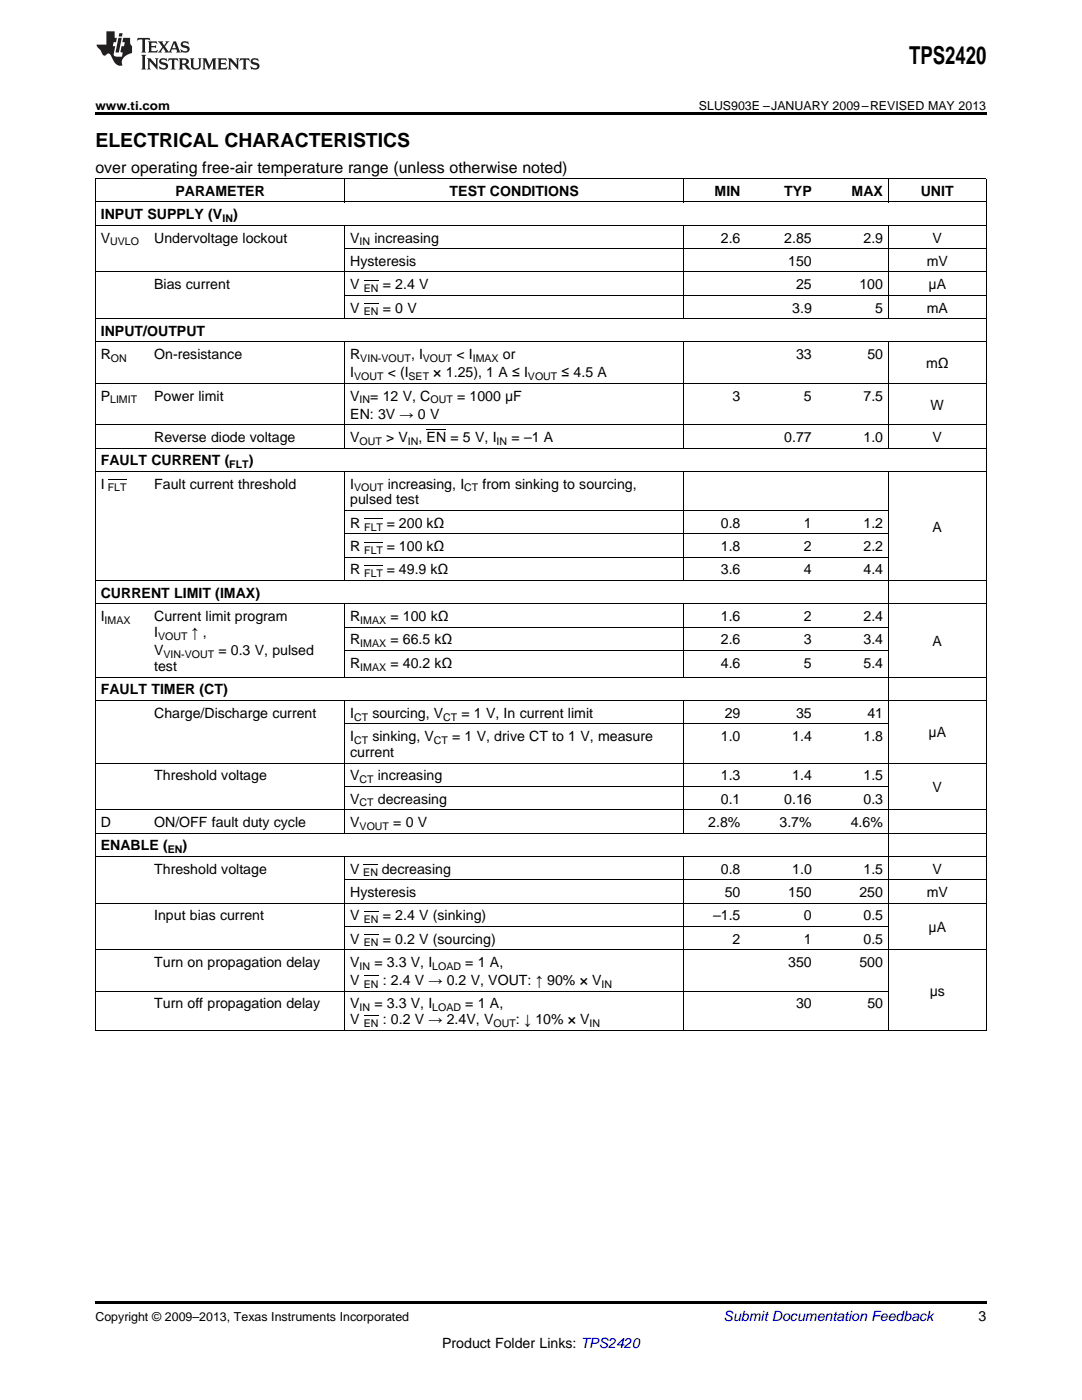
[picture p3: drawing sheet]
<svg xmlns="http://www.w3.org/2000/svg" width="216mm" height="279mm" viewBox="0 0 216 279" stroke-linecap="round" stroke-linejoin="round" font-family="sans-serif">
<defs><g id="words">
<text font-size="4.9" x="181.4" y="12.8">TPS2420</text>
<text font-size="3.9" x="19" y="29.3">ELECTRICAL CHARACTERISTICS</text>
<text font-size="3.2" x="19" y="34.4">over operating free-air temperature range (unless otherwise noted)</text>
<g font-size="2.8">
<text x="35" y="39.1">PARAMETER</text>
<text x="89.7" y="39.1">TEST CONDITIONS</text>
<text x="142.6" y="39.1">MIN</text>
<text x="156.5" y="39.1">TYP</text>
<text x="169.9" y="39.1">MAX</text>
<text x="183.7" y="39.1">UNIT</text>
<text x="20.1" y="43.7">INPUT SUPPLY (V</text>
<text x="46.5" y="43.7">)</text>
<text x="20.1" y="48.4">V</text>
<text x="30.8" y="48.4">Undervoltage lockout</text>
<text x="69.9" y="48.4">V</text>
<text x="69.9" y="53.1">Hysteresis</text>
<text x="74.7" y="48.4">increasing</text>
<text x="143.8" y="48.4">2.6</text>
<text x="156.5" y="48.4">2.85</text>
<text x="157.3" y="53.1">150</text>
<text x="172.3" y="48.4">2.9</text>
<text x="184.9" y="53.1">mV</text>
<text x="186.1" y="48.4">V</text>
<text x="30.8" y="57.7">Bias current</text>
<text x="69.9" y="57.7">V</text>
<text x="76.4" y="57.7">= 2.4 V</text>
<text x="158.9" y="57.7">25</text>
<text x="171.5" y="57.7">100</text>
<text x="185.3" y="57.7">μA</text>
<text x="69.9" y="62.4">V</text>
<text x="76.4" y="62.4">= 0 V</text>
<text x="158.1" y="62.4">3.9</text>
<text x="174.6" y="62.4">5</text>
<text x="184.9" y="62.4">mA</text>
<text x="20.1" y="67">INPUT/OUTPUT</text>
<text x="20.1" y="71.7">R</text>
<text x="30.8" y="71.7">On-resistance</text>
<text x="69.9" y="71.7">R</text>
<text x="82" y="71.7">, I</text>
<text x="91.1" y="71.7">&lt; I</text>
<text x="100.3" y="71.7">or</text>
<text x="158.9" y="71.7">33</text>
<text x="173.1" y="71.7">50</text>
<text x="69.9" y="75.3">I</text>
<text x="77.4" y="75.3">&lt; (I</text>
<text x="86.5" y="75.3">× 1.25), 1 A ≤ I</text>
<text x="112" y="75.3">≤ 4.5 A</text>
<text x="184.8" y="73.5">mΩ</text>
<text x="20.1" y="79.9">P</text>
<text x="30.8" y="79.9">Power limit</text>
<text x="69.9" y="79.9">V</text>
<text x="69.9" y="83.5">EN: 3V → 0 V</text>
<text x="73.9" y="79.9">= 12 V, C</text>
<text x="91.2" y="79.9">= 1000 μF</text>
<text x="146.2" y="79.9">3</text>
<text x="160.4" y="79.9">5</text>
<text x="172.3" y="79.9">7.5</text>
<text x="185.7" y="81.7">W</text>
<text x="30.8" y="88.2">Reverse diode voltage</text>
<text x="69.9" y="88.2">V</text>
<text x="77" y="88.2">&gt; V</text>
<text x="83.5" y="88.2">, EN = 5 V, I</text>
<text x="102.1" y="88.2">= –1 A</text>
<text x="156.5" y="88.2">0.77</text>
<text x="172.3" y="88.2">1.0</text>
<text x="186.1" y="88.2">V</text>
<text x="20.1" y="92.9">FAULT CURRENT (</text>
<text x="49.6" y="92.9">)</text>
<text x="20.1" y="97.5">I</text>
<text x="30.8" y="97.5">Fault current threshold</text>
<text x="69.9" y="97.5">I</text>
<text x="69.9" y="100.7">pulsed test</text>
<text x="77.4" y="97.5">increasing, I</text>
<text x="96.3" y="97.5">from sinking to sourcing,</text>
<text x="69.9" y="105.3">R</text>
<text x="77.2" y="105.3">= 200 kΩ</text>
<text x="143.8" y="105.3">0.8</text>
<text x="160.4" y="105.3">1</text>
<text x="172.3" y="105.3">1.2</text>
<text x="186.1" y="106.1">A</text>
<text x="69.9" y="110">R</text>
<text x="77.2" y="110">= 100 kΩ</text>
<text x="143.8" y="110">1.8</text>
<text x="160.4" y="110">2</text>
<text x="172.3" y="110">2.2</text>
<text x="20.1" y="119.3">CURRENT LIMIT (IMAX)</text>
<text x="69.9" y="114.7">R</text>
<text x="77.2" y="114.7">= 49.9 kΩ</text>
<text x="143.8" y="114.7">3.6</text>
<text x="160.4" y="114.7">4</text>
<text x="172.3" y="114.7">4.4</text>
<text x="20.1" y="124">I</text>
<text x="30.8" y="124">Current limit program</text>
<text x="69.9" y="124">R</text>
<text x="77.9" y="124">= 100 kΩ</text>
<text x="143.8" y="124">1.6</text>
<text x="160.4" y="124">2</text>
<text x="172.3" y="124">2.4</text>
<text x="30.8" y="127.1">I</text>
<text x="30.8" y="130.7">V</text>
<text x="38.2" y="127.1">↑ ,</text>
<text x="43.6" y="130.7">= 0.3 V, pulsed</text>
<text x="69.9" y="128.6">R</text>
<text x="77.9" y="128.6">= 66.5 kΩ</text>
<text x="143.8" y="128.6">2.6</text>
<text x="160.4" y="128.6">3</text>
<text x="172.3" y="128.6">3.4</text>
<text x="186.1" y="128.9">A</text>
<text x="30.8" y="133.9">test</text>
<text x="69.9" y="133.3">R</text>
<text x="77.9" y="133.3">= 40.2 kΩ</text>
<text x="143.8" y="133.3">4.6</text>
<text x="160.4" y="133.3">5</text>
<text x="172.3" y="133.3">5.4</text>
<text x="20.1" y="138.6">FAULT TIMER (CT)</text>
<text x="30.8" y="143.2">Charge/Discharge current</text>
<text x="69.9" y="143.2">I</text>
<text x="74.3" y="143.2">sourcing, V</text>
<text x="92.1" y="143.2">= 1 V, In current limit</text>
<text x="144.6" y="143.2">29</text>
<text x="158.9" y="143.2">35</text>
<text x="173.1" y="143.2">41</text>
<text x="69.9" y="147.9">I</text>
<text x="74.3" y="147.9">sinking, V</text>
<text x="90.2" y="147.9">= 1 V, drive CT to 1 V, measure</text>
<text x="143.8" y="147.9">1.0</text>
<text x="158.1" y="147.9">1.4</text>
<text x="172.3" y="147.9">1.8</text>
<text x="185.3" y="147.1">μA</text>
<text x="30.8" y="155.7">Threshold voltage</text>
<text x="69.9" y="151.1">current</text>
<text x="69.9" y="155.7">V</text>
<text x="75.4" y="155.7">increasing</text>
<text x="143.8" y="155.7">1.3</text>
<text x="158.1" y="155.7">1.4</text>
<text x="172.3" y="155.7">1.5</text>
<text x="69.9" y="160.4">V</text>
<text x="75.4" y="160.4">decreasing</text>
<text x="143.8" y="160.4">0.1</text>
<text x="156.5" y="160.4">0.16</text>
<text x="172.3" y="160.4">0.3</text>
<text x="186.1" y="158">V</text>
<text x="20.1" y="165">D</text>
<text x="30.8" y="165">ON/OFF fault duty cycle</text>
<text x="69.9" y="165">V</text>
<text x="78.5" y="165">= 0 V</text>
<text x="141.3" y="165">2.8%</text>
<text x="155.5" y="165">3.7%</text>
<text x="169.8" y="165">4.6%</text>
<text x="20.1" y="169.7">ENABLE (</text>
<text x="36.4" y="169.7">)</text>
<text x="30.8" y="174.3">Threshold voltage</text>
<text x="69.9" y="174.3">V</text>
<text x="69.9" y="179">Hysteresis</text>
<text x="76.2" y="174.3">decreasing</text>
<text x="143.8" y="174.3">0.8</text>
<text x="144.6" y="179">50</text>
<text x="157.3" y="179">150</text>
<text x="158.1" y="174.3">1.0</text>
<text x="171.5" y="179">250</text>
<text x="172.3" y="174.3">1.5</text>
<text x="184.9" y="179">mV</text>
<text x="186.1" y="174.3">V</text>
<text x="30.8" y="183.7">Input bias current</text>
<text x="69.9" y="183.7">V</text>
<text x="76.4" y="183.7">= 2.4 V (sinking)</text>
<text x="142.3" y="183.7">–1.5</text>
<text x="160.4" y="183.7">0</text>
<text x="172.3" y="183.7">0.5</text>
<text x="185.3" y="186">μA</text>
<text x="69.9" y="188.3">V</text>
<text x="76.4" y="188.3">= 0.2 V (sourcing)</text>
<text x="146.2" y="188.3">2</text>
<text x="160.4" y="188.3">1</text>
<text x="172.3" y="188.3">0.5</text>
<text x="30.8" y="193">Turn on propagation delay</text>
<text x="69.9" y="193">V</text>
<text x="69.9" y="196.6">V</text>
<text x="74.7" y="193">= 3.3 V, I</text>
<text x="76.4" y="196.6">: 2.4 V → 0.2 V, VOUT: ↑ 90% × V</text>
<text x="92.9" y="193">= 1 A,</text>
<text x="157.3" y="193">350</text>
<text x="171.5" y="193">500</text>
<text x="30.8" y="201.2">Turn off propagation delay</text>
<text x="69.9" y="201.2">V</text>
<text x="74.7" y="201.2">= 3.3 V, I</text>
<text x="92.9" y="201.2">= 1 A,</text>
<text x="158.9" y="201.2">30</text>
<text x="173.1" y="201.2">50</text>
<text x="185.5" y="198.7">μs</text>
<text x="69.9" y="204.4">V</text>
<text x="76.4" y="204.4">: 0.2 V → 2.4V, V</text>
<text x="102.9" y="204.4">: ↓ 10% × V</text>
<text x="195.3" y="263.6">3</text>
<text x="88.2" y="269">Product Folder Links: TPS2420</text>
</g>
<text font-size="2.8" fill="#0000c8" x="144.4" y="263.6">Submit Documentation Feedback</text>
<g font-size="2.5">
<text x="19" y="21.9">www.ti.com</text>
<text x="139.5" y="21.9">SLUS903E –JANUARY 2009–REVISED MAY 2013</text>
<text x="19" y="263.6">Copyright © 2009–2013, Texas Instruments Incorporated</text>
</g>
<g font-size="2.1">
<text x="44.4" y="44.3">IN</text>
<text x="22" y="49">UVLO</text>
<text x="71.8" y="49">IN</text>
<text x="72.6" y="58.3">EN</text>
<text x="72.6" y="62.9">EN</text>
<text x="22.1" y="72.2">ON</text>
<text x="70.7" y="75.8">VOUT</text>
<text x="71.9" y="72.2">VIN-VOUT</text>
<text x="81.5" y="75.8">SET</text>
<text x="84.4" y="72.2">VOUT</text>
<text x="94.3" y="72.2">IMAX</text>
<text x="105.3" y="75.8">VOUT</text>
<text x="22" y="80.5">LIMIT</text>
<text x="71.8" y="80.5">IN</text>
<text x="85.9" y="80.5">OUT</text>
<text x="71.8" y="88.8">OUT</text>
<text x="81.4" y="88.8">IN</text>
<text x="99.1" y="88.8">IN</text>
<text x="45.8" y="93.4">FLT</text>
<text x="21.5" y="98.1">FLT</text>
<text x="70.7" y="98.1">VOUT</text>
<text x="92.6" y="98.1">CT</text>
<text x="72.7" y="105.9">FLT</text>
<text x="72.7" y="110.6">FLT</text>
<text x="72.7" y="115.2">FLT</text>
<text x="20.9" y="124.5">IMAX</text>
<text x="71.9" y="124.5">IMAX</text>
<text x="31.5" y="127.7">VOUT</text>
<text x="32.6" y="131.3">VIN-VOUT</text>
<text x="71.9" y="129.2">IMAX</text>
<text x="71.9" y="133.8">IMAX</text>
<text x="70.7" y="143.8">CT</text>
<text x="88.4" y="143.8">CT</text>
<text x="70.7" y="148.4">CT</text>
<text x="86.6" y="148.4">CT</text>
<text x="71.8" y="156.3">CT</text>
<text x="71.8" y="160.9">CT</text>
<text x="71.8" y="165.6">VOUT</text>
<text x="33.5" y="170.3">EN</text>
<text x="72.5" y="174.9">EN</text>
<text x="72.6" y="184.2">EN</text>
<text x="72.6" y="188.9">EN</text>
<text x="71.8" y="193.5">IN</text>
<text x="72.6" y="197.1">EN</text>
<text x="86.3" y="193.5">LOAD</text>
<text x="120" y="197.1">IN</text>
<text x="71.8" y="201.8">IN</text>
<text x="86.3" y="201.8">LOAD</text>
<text x="72.6" y="205">EN</text>
<text x="98.5" y="205">OUT</text>
<text x="117.7" y="205">IN</text>
</g>
</g></defs>
<path d="M19 22.5h177.8v.5h-177.8zM19 259.7h177.8v.5h-177.8z" fill="#000"/>
<g fill="none" stroke="#000" stroke-width=".2">
<path d="M19 35.6h177.8M19.1 35.7v170M68.8 35.7v4.7M136.3 35.7v4.7M177.2 35.7v4.7M196.8 35.7v170M19 54.3h177.8M19 45h177.8M19 40.3h177.8M68.8 45v18.6M68.8 58.9h128M68.8 49.6h128"/>
<path d="M136.3 45v18.6M177.2 45v18.6M19 76.5h177.8M19 68.2h177.8M19 63.6h177.8M68.8 68.3v21.2M136.3 68.3v21.2M177.2 68.3v21.2M19 94.1h177.8M19 89.4h177.8M19 84.8h177.8M68.8 94.1v21.8"/>
<path d="M136.3 94.1v21.8M177.2 94.1v111.6M19 115.9h177.8M68.8 111.2h108.5M68.8 106.6h108.5M68.8 101.9h108.5M19 139.8h177.8M19 135.1h177.8M19 120.5h177.8M68.8 120.6v14.6M68.8 139.8v26.5M68.8 129.8h108.5"/>
<path d="M68.8 125.2h108.5M136.3 120.6v14.6M136.3 139.8v26.5M19 152.3h177.8M68.8 156.9h108.5M68.8 144.4h108.5M19 170.9h177.8M19 166.2h177.8M19 161.6h177.8M68.8 171v34.7M68.8 175.6h128M136.3 171v34.7"/>
<path d="M19 197.8h158.3M19 189.5h177.8M19 180.2h177.8M68.8 184.9h108.5M19 205.6h177.8"/>
</g>
<g fill="#231f20">
<path d="M27.5 7.6l-.1 .5 .4-.2h.6v.1v2.1l-.2 .4h1l-.3-.4v-2.1l.1-.1h.5l.5 .2-.2-.5zM29.5 8.3l.2 .3v1.5l-.2 .4h1.8l.2-.6a1.04 1.04 0 0 1-1.3 .2v-.7h.6l.3 .2v-.6l-.3 .2h-.6v-.6l.8-.1 .4 .3-.2-.5zM31.5 8.3l.9 1.1-.9 1.1h.8l-.2-.2 .5-.7 .4 .7-.2 .2h1.5l-.1-.2 .1-.4h.9l.1 .4-.2 .2h1l-.3-.3-.7-1.9h-.5l-.9 2-.8-1 .9-1h-.8l.1 .3-.3 .5-.4-.6 .2-.2zM34.7 8.6l.4 1h-.7zM36.3 8.4a.63 .63 0 0 0-.2 .7 .63 .63 0 0 0 .6 .4l.6 .2 .1 .2a.75 .75 0 0 1-.7 .4 .75 .75 0 0 1-.6-.5l.1 .7 .1-.1a1.11 1.11 0 0 0 1.5-.6 1.13 1.13 0 0 0-1.2-.8l-.1-.4a1.04 1.04 0 0 1 1.2 .2l-.2-.5-.1 .1-.5-.2zM28.2 10.9l.2 .4v2.2l-.2 .4h1l-.3-.4v-2.2l.3-.4zM29.3 11.6l.3 .4v1.5l-.3 .4h.8l-.2-.4v-1.3l1.5 1.7v-1.9l.2-.4h-.7l.2 .4v.9l-1.1-1.3zM32 11.8a.62 .62 0 0 0-.2 .7 .62 .62 0 0 0 .6 .4l.6 .1 .1 .3a.76 .76 0 0 1-.7 .3 .76 .76 0 0 1-.6-.4l.1 .7 .1-.1a1.11 1.11 0 0 0 1.5-.6 1.13 1.13 0 0 0-1.2-.8l-.1-.4a1.04 1.04 0 0 1 1.2 .2l-.2-.6-.1 .1-.5-.1zM33.7 11.6l-.2 .6a.61 .61 0 0 1 .8-.3v1.6l-.2 .4h.9l-.2-.4v-1.6a.63 .63 0 0 1 .8 .3l-.2-.6zM35.6 11.6l.3 .4v1.5l-.3 .4h1l-.2-.2v-.8l.5 .2a.76 .76 0 0 0 1.2 .7l-1-1a.58 .58 0 0 0 .6-.5 .58 .58 0 0 0-.5-.6zM36.4 11.9h.1a.45 .45 0 0 1 .5 .1 .45 .45 0 0 1 .1 .5l-.7 .2zM37.9 11.6l.2 .2a2.17 2.17 0 0 0 .3 1.9 .99 .99 0 0 0 1.6-.6v-1.1l.2-.4h-.7l.2 .2a1.92 1.92 0 0 1-.2 1.8 .6 .6 0 0 1-.9-.5v-1.1l.2-.4zM40.4 11.6l.2 .4v1.5l-.2 .4h.7l-.2-.4v-1.4l.8 1.8 .8-1.8v1.4l-.2 .4h.9l-.2-.4v-1.5l.2-.4h-.8l-.6 1.5-.6-1.5zM43.4 11.6l.2 .4v1.5l-.2 .4h1.8l.2-.6a1.04 1.04 0 0 1-1.3 .1v-.6h.5l.4 .2v-.6l-.4 .2h-.5v-.7h.8l.3 .3-.1-.6zM45.5 11.6l.2 .4v1.5l-.2 .4h.7l-.2-.4v-1.3l1.5 1.7v-1.9l.2-.4h-.7l.2 .4v.9l-1.1-1.3zM47.9 11.6l-.1 .6a.61 .61 0 0 1 .8-.3v1.6l-.3 .4h1l-.3-.4 .1-1.6a.63 .63 0 0 1 .7 .3l-.1-.6zM50.2 11.8a.62 .62 0 0 0-.2 .7 .62 .62 0 0 0 .6 .4l.6 .1 .2 .3a.76 .76 0 0 1-.8 .3 .76 .76 0 0 1-.6-.4l.1 .7 .2-.1a1.11 1.11 0 0 0 1.5-.6 1.13 1.13 0 0 0-1.3-.8l-.1-.4a1.04 1.04 0 0 1 1.2 .2l-.1-.6-.2 .1-.5-.1z"/>
<path d="M21.2 6.3v2.6h-1.9l.1 .4 .7 .9a.91 .91 0 0 0 1 .8 .56 .56 0 0 1 .5-.3 .56 .56 0 0 1 .5 .3l.4 .8a1.53 1.53 0 0 0 1.9 1.2 1.54 1.54 0 0 1 1-2.1l.9-.3v-1.4a1.52 1.52 0 0 1-.3-1.6h-1.4l-.2 .8h.5l-.2 .8h-.4l-.2 1v.2l.4 .1-.2 .8a1.93 1.93 0 0 1-1.6-.3l.3-1.8h-.5l.2-.8h.4l.2-.8h-.4v-1.3zM23.6 7.6l-.6 2.9h.7l.6-2.9zM23.8 6.6l-.1 .7h.6l.2-.7z"/>
</g>
<path d="M72.6 55.9h2.9M72.6 60.6h2.9M21.5 95.7h3.8M85.1 85.7h3.9M72.7 112.8h3.7M72.7 108.2h3.7M72.7 103.5h3.7M72.5 172.5h2.9M72.6 194.8h2.9M72.6 186.5h2.9M72.6 181.8h2.9M72.6 202.6h2.9" fill="none" stroke="#000" stroke-width=".2"/>
<use href="#words"/>
</svg>
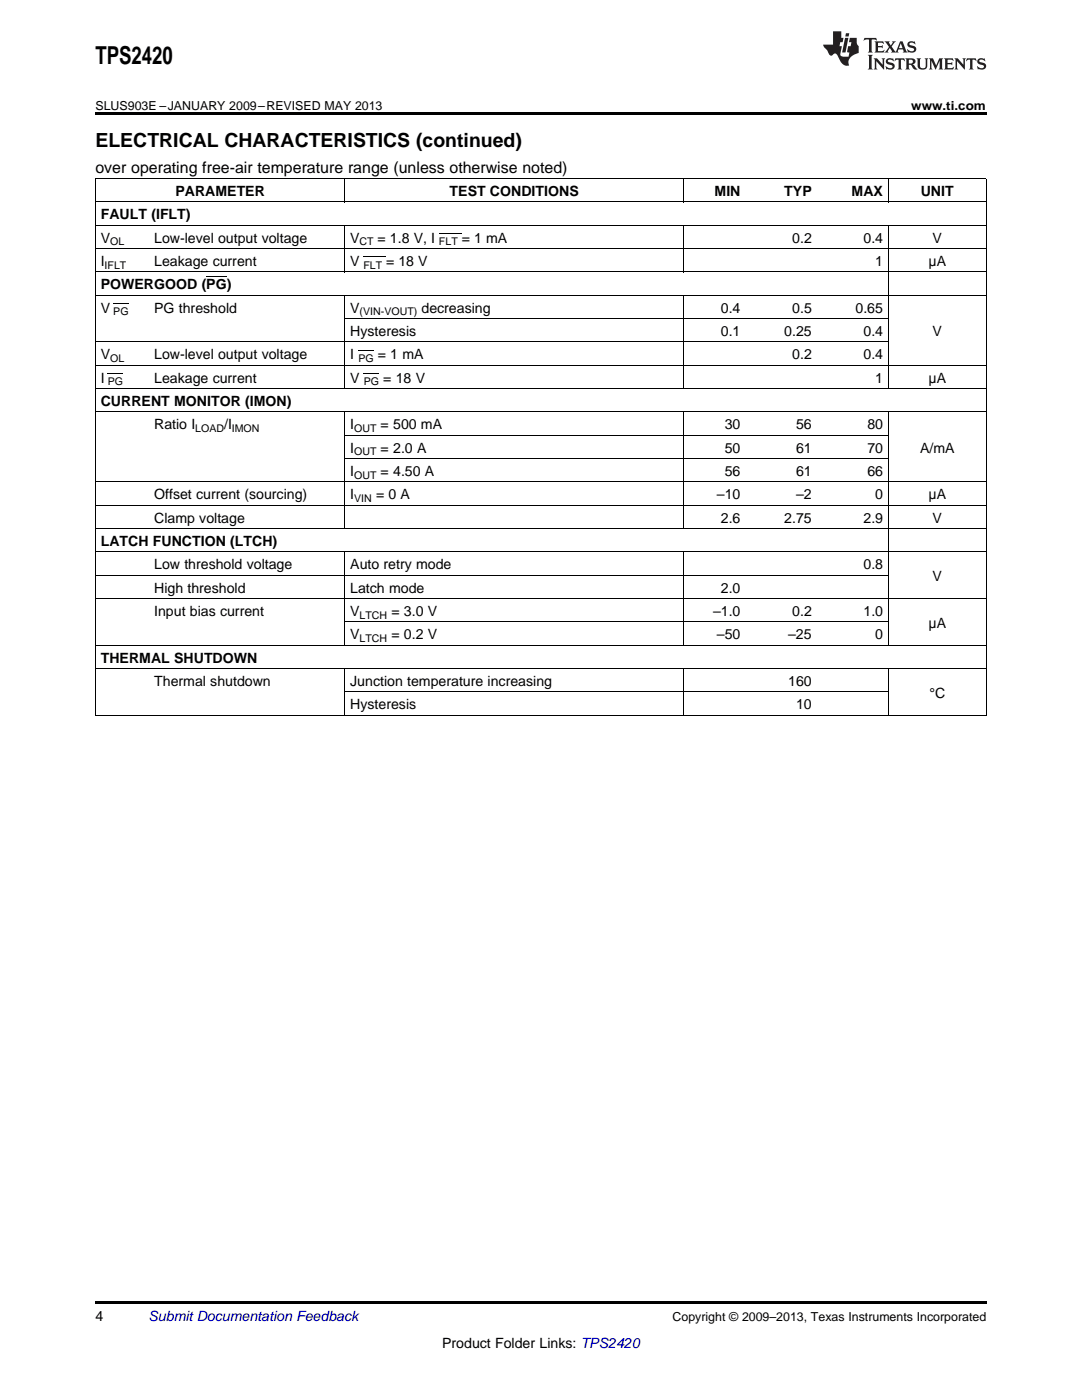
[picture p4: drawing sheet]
<svg xmlns="http://www.w3.org/2000/svg" width="216mm" height="279mm" viewBox="0 0 216 279" stroke-linecap="round" stroke-linejoin="round" font-family="sans-serif">
<defs><g id="words">
<text font-size="4.9" x="19" y="12.8">TPS2420</text>
<text font-size="3.9" x="19" y="29.3">ELECTRICAL CHARACTERISTICS (continued)</text>
<text font-size="3.2" x="19" y="34.4">over operating free-air temperature range (unless otherwise noted)</text>
<g font-size="2.8">
<text x="35" y="39.1">PARAMETER</text>
<text x="89.7" y="39.1">TEST CONDITIONS</text>
<text x="142.6" y="39.1">MIN</text>
<text x="156.5" y="39.1">TYP</text>
<text x="169.9" y="39.1">MAX</text>
<text x="183.7" y="39.1">UNIT</text>
<text x="20.1" y="43.7">FAULT (IFLT)</text>
<text x="20.1" y="48.4">V</text>
<text x="20.1" y="53.1">I</text>
<text x="30.8" y="48.4">Low-level output voltage</text>
<text x="30.8" y="53.1">Leakage current</text>
<text x="69.9" y="48.4">V</text>
<text x="69.9" y="53.1">V</text>
<text x="75.4" y="48.4">= 1.8 V, I</text>
<text x="77.1" y="53.1">= 18 V</text>
<text x="92.2" y="48.4">= 1 mA</text>
<text x="158.1" y="48.4">0.2</text>
<text x="172.3" y="48.4">0.4</text>
<text x="174.6" y="53.1">1</text>
<text x="185.3" y="53.1">μA</text>
<text x="186.1" y="48.4">V</text>
<text x="20.1" y="57.7">POWERGOOD (PG)</text>
<text x="20.1" y="62.4">V</text>
<text x="30.8" y="62.4">PG threshold</text>
<text x="69.9" y="62.4">V</text>
<text x="84.1" y="62.4">decreasing</text>
<text x="143.8" y="62.4">0.4</text>
<text x="158.1" y="62.4">0.5</text>
<text x="170.7" y="62.4">0.65</text>
<text x="20.1" y="71.7">V</text>
<text x="30.8" y="71.7">Low-level output voltage</text>
<text x="69.9" y="67">Hysteresis</text>
<text x="69.9" y="71.7">I</text>
<text x="75.4" y="71.7">= 1 mA</text>
<text x="143.8" y="67">0.1</text>
<text x="156.5" y="67">0.25</text>
<text x="158.1" y="71.7">0.2</text>
<text x="172.3" y="67">0.4</text>
<text x="172.3" y="71.7">0.4</text>
<text x="186.1" y="67">V</text>
<text x="20.1" y="76.3">I</text>
<text x="30.8" y="76.3">Leakage current</text>
<text x="69.9" y="76.3">V</text>
<text x="76.5" y="76.3">= 18 V</text>
<text x="174.6" y="76.3">1</text>
<text x="185.3" y="76.3">μA</text>
<text x="20.1" y="81">CURRENT MONITOR (IMON)</text>
<text x="30.8" y="85.7">Ratio I</text>
<text x="44.7" y="85.7">/I</text>
<text x="69.9" y="85.7">I</text>
<text x="76" y="85.7">= 500 mA</text>
<text x="144.6" y="85.7">30</text>
<text x="158.9" y="85.7">56</text>
<text x="173.1" y="85.7">80</text>
<text x="69.9" y="90.3">I</text>
<text x="69.9" y="95">I</text>
<text x="76" y="90.3">= 2.0 A</text>
<text x="76" y="95">= 4.50 A</text>
<text x="144.6" y="90.3">50</text>
<text x="144.6" y="95">56</text>
<text x="158.9" y="90.3">61</text>
<text x="158.9" y="95">61</text>
<text x="173.1" y="90.3">70</text>
<text x="173.1" y="95">66</text>
<text x="183.6" y="90.3">A/mA</text>
<text x="30.8" y="99.6">Offset current (sourcing)</text>
<text x="69.9" y="99.6">I</text>
<text x="75" y="99.6">= 0 A</text>
<text x="143.1" y="99.6">–10</text>
<text x="158.9" y="99.6">–2</text>
<text x="174.6" y="99.6">0</text>
<text x="185.3" y="99.6">μA</text>
<text x="30.8" y="104.3">Clamp voltage</text>
<text x="143.8" y="104.3">2.6</text>
<text x="156.5" y="104.3">2.75</text>
<text x="172.3" y="104.3">2.9</text>
<text x="186.1" y="104.3">V</text>
<text x="20.1" y="108.9">LATCH FUNCTION (LTCH)</text>
<text x="30.8" y="113.6">Low threshold voltage</text>
<text x="69.9" y="113.6">Auto retry mode</text>
<text x="172.3" y="113.6">0.8</text>
<text x="30.8" y="118.3">High threshold</text>
<text x="69.9" y="118.3">Latch mode</text>
<text x="143.8" y="118.3">2.0</text>
<text x="186.1" y="115.9">V</text>
<text x="30.8" y="122.9">Input bias current</text>
<text x="69.9" y="122.9">V</text>
<text x="78.1" y="122.9">= 3.0 V</text>
<text x="142.3" y="122.9">–1.0</text>
<text x="158.1" y="122.9">0.2</text>
<text x="172.3" y="122.9">1.0</text>
<text x="185.3" y="125.2">μA</text>
<text x="69.9" y="127.6">V</text>
<text x="78.1" y="127.6">= 0.2 V</text>
<text x="143.1" y="127.6">–50</text>
<text x="157.3" y="127.6">–25</text>
<text x="174.6" y="127.6">0</text>
<text x="20.1" y="132.2">THERMAL SHUTDOWN</text>
<text x="30.8" y="136.9">Thermal shutdown</text>
<text x="69.9" y="136.9">Junction temperature increasing</text>
<text x="157.3" y="136.9">160</text>
<text x="69.9" y="141.5">Hysteresis</text>
<text x="158.9" y="141.5">10</text>
<text x="185.5" y="139.2">°C</text>
<text x="19" y="263.6">4</text>
<text x="88.2" y="269">Product Folder Links: TPS2420</text>
</g>
<text font-size="2.8" fill="#0000c8" x="29.6" y="263.6">Submit Documentation Feedback</text>
<g font-size="2.5">
<text x="19" y="21.9">SLUS903E –JANUARY 2009–REVISED MAY 2013</text>
<text x="181.8" y="21.9">www.ti.com</text>
<text x="134.2" y="263.6">Copyright © 2009–2013, Texas Instruments Incorporated</text>
</g>
<g font-size="2.1">
<text x="20.9" y="53.6">IFLT</text>
<text x="22" y="49">OL</text>
<text x="71.8" y="49">CT</text>
<text x="72.5" y="53.6">FLT</text>
<text x="87.6" y="49">FLT</text>
<text x="22.6" y="62.9">PG</text>
<text x="71.8" y="62.9">(VIN-VOUT)</text>
<text x="21.5" y="76.9">PG</text>
<text x="22" y="72.2">OL</text>
<text x="71.5" y="72.2">PG</text>
<text x="72.6" y="76.9">PG</text>
<text x="38.9" y="86.2">LOAD</text>
<text x="46.2" y="86.2">IMON</text>
<text x="70.7" y="86.2">OUT</text>
<text x="70.7" y="90.9">OUT</text>
<text x="70.7" y="95.5">OUT</text>
<text x="70.7" y="100.2">VIN</text>
<text x="71.8" y="123.5">LTCH</text>
<text x="71.8" y="128.1">LTCH</text>
</g>
</g></defs>
<path d="M19 22.5h177.8v.5h-177.8zM19 259.7h177.8v.5h-177.8z" fill="#000"/>
<g fill="none" stroke="#000" stroke-width=".2">
<path d="M19 35.6h177.8M19.1 35.7v107.1M68.8 35.7v4.7M136.3 35.7v4.7M177.2 35.7v4.7M196.8 35.7v107.1M19 58.9h177.8M19 54.3h177.8M19 49.6h177.8M19 45h177.8M19 40.3h177.8M68.8 45v9.3"/>
<path d="M68.8 59v18.6M136.3 45v9.3M136.3 59v18.6M177.2 45v32.6M19 77.6h177.8M19 72.9h177.8M19 68.2h158.3M68.8 63.6h108.5M19 96.2h177.8M19 82.2h177.8M68.8 82.3v23.3M68.8 91.5h108.5"/>
<path d="M68.8 86.9h108.5M136.3 82.3v23.3M177.2 82.3v46.5M19 119.5h177.8M19 114.8h158.3M19 110.2h177.8M19 105.5h177.8M19 100.8h177.8M68.8 110.2v18.6M136.3 110.2v18.6M19 133.4h177.8M19 128.8h177.8"/>
<path d="M68.8 133.5v9.3M68.8 138.1h108.5M68.8 124.1h108.5M136.3 133.5v9.3M177.2 133.5v9.3M19 142.8h177.8"/>
</g>
<g fill="#231f20">
<path d="M172.5 7.6l-.1 .5 .4-.2h.6v.1v2.1l-.2 .4h.9l-.2-.4v-2.1l.1-.1h.5l.5 .2-.2-.5zM174.5 8.3l.2 .3v1.5l-.2 .4h1.8l.2-.6a1.04 1.04 0 0 1-1.3 .2v-.7h.6l.3 .2v-.6l-.3 .2h-.6v-.6l.8-.1 .4 .3-.2-.5zM176.5 8.3l.9 1.1-.9 1.1h.8l-.2-.2 .4-.7 .5 .7-.2 .2h1.5l-.2-.2 .2-.4h.9l.1 .4-.2 .2h1l-.3-.3-.7-1.9h-.5l-.9 2-.8-1 .9-1h-.8l.1 .3-.4 .5-.3-.6 .1-.2zM179.7 8.6l.4 1h-.7zM181.3 8.4a.63 .63 0 0 0-.2 .7 .63 .63 0 0 0 .6 .4l.6 .2 .1 .2a.75 .75 0 0 1-.7 .4 .75 .75 0 0 1-.6-.5l.1 .7 .1-.1a1.11 1.11 0 0 0 1.5-.6 1.13 1.13 0 0 0-1.2-.8l-.1-.4a1.04 1.04 0 0 1 1.2 .2l-.2-.5-.2 .1-.4-.2zM173.2 10.9l.2 .4v2.2l-.2 .4h1l-.3-.4v-2.2l.3-.4zM174.3 11.6l.3 .4v1.5l-.3 .4h.8l-.2-.4v-1.3l1.5 1.7v-1.9l.2-.4h-.7l.2 .4v.9l-1.1-1.3zM177 11.8a.62 .62 0 0 0-.2 .7 .62 .62 0 0 0 .6 .4l.6 .1 .1 .3a.76 .76 0 0 1-.7 .3 .76 .76 0 0 1-.7-.4l.2 .7 .1-.1a1.11 1.11 0 0 0 1.5-.6 1.13 1.13 0 0 0-1.2-.8l-.1-.4a1.04 1.04 0 0 1 1.2 .2l-.2-.6-.2 .1-.5-.1zM178.7 11.6l-.2 .6a.61 .61 0 0 1 .8-.3v1.6l-.2 .4h.9l-.2-.4v-1.6a.63 .63 0 0 1 .7 .3l-.1-.6zM180.6 11.6l.3 .4v1.5l-.3 .4h1l-.2-.2-.1-.8 .6 .2a.76 .76 0 0 0 1.2 .7l-1-1a.58 .58 0 0 0 .6-.5 .58 .58 0 0 0-.5-.6zM181.4 11.9h.1a.45 .45 0 0 1 .5 .1 .45 .45 0 0 1 .1 .5l-.8 .2zM182.9 11.6l.2 .2a2.17 2.17 0 0 0 .3 1.9 .99 .99 0 0 0 1.6-.6v-1.1l.2-.4h-.7l.2 .2a1.92 1.92 0 0 1-.2 1.8 .6 .6 0 0 1-.9-.5v-1.1l.2-.4zM185.4 11.6l.2 .4v1.5l-.2 .4h.7l-.2-.4v-1.4l.8 1.8 .8-1.8v1.4l-.2 .4h.9l-.2-.4v-1.5l.2-.4h-.8l-.6 1.5-.6-1.5zM188.4 11.6l.2 .4v1.5l-.2 .4h1.8l.1-.6a1.04 1.04 0 0 1-1.2 .1v-.6h.5l.4 .2v-.6l-.4 .2h-.5v-.7h.8l.3 .3-.1-.6zM190.5 11.6l.2 .4v1.5l-.2 .4h.7l-.2-.4v-1.3l1.5 1.7v-1.9l.2-.4h-.7l.2 .4v.9l-1.1-1.3zM192.9 11.6l-.1 .6a.61 .61 0 0 1 .7-.3l.1 1.6-.3 .4h1l-.3-.4 .1-1.6a.63 .63 0 0 1 .7 .3l-.1-.6zM195.2 11.8a.62 .62 0 0 0-.2 .7 .62 .62 0 0 0 .6 .4l.6 .1 .1 .3a.76 .76 0 0 1-.7 .3 .76 .76 0 0 1-.6-.4l.1 .7 .1-.1a1.11 1.11 0 0 0 1.6-.6 1.13 1.13 0 0 0-1.3-.8l-.1-.4a1.04 1.04 0 0 1 1.2 .2l-.1-.6-.2 .1-.5-.1z"/>
<path d="M166.2 6.3v2.6h-1.9v.4l.8 .9a.91 .91 0 0 0 1 .8 .56 .56 0 0 1 .5-.3 .56 .56 0 0 1 .5 .3l.4 .8a1.53 1.53 0 0 0 1.9 1.2 1.54 1.54 0 0 1 1-2.1l.9-.3v-1.4a1.52 1.52 0 0 1-.4-1.6h-1.3l-.2 .8h.5l-.2 .8h-.5l-.1 1v.2l.4 .1-.2 .8a1.93 1.93 0 0 1-1.6-.3l.3-1.8h-.5l.2-.8h.4l.2-.8h-.4v-1.3zM168.6 7.6l-.6 2.9h.7l.6-2.9zM168.8 6.6l-.1 .7h.6l.2-.7z"/>
</g>
<path d="M41.2 55.2h4M72.5 51.2h4.5M87.6 46.6h4.5M21.5 74.5h3.1M22.6 60.6h3M71.5 69.9h3M72.6 74.5h3" fill="none" stroke="#000" stroke-width=".2"/>
<use href="#words"/>
</svg>
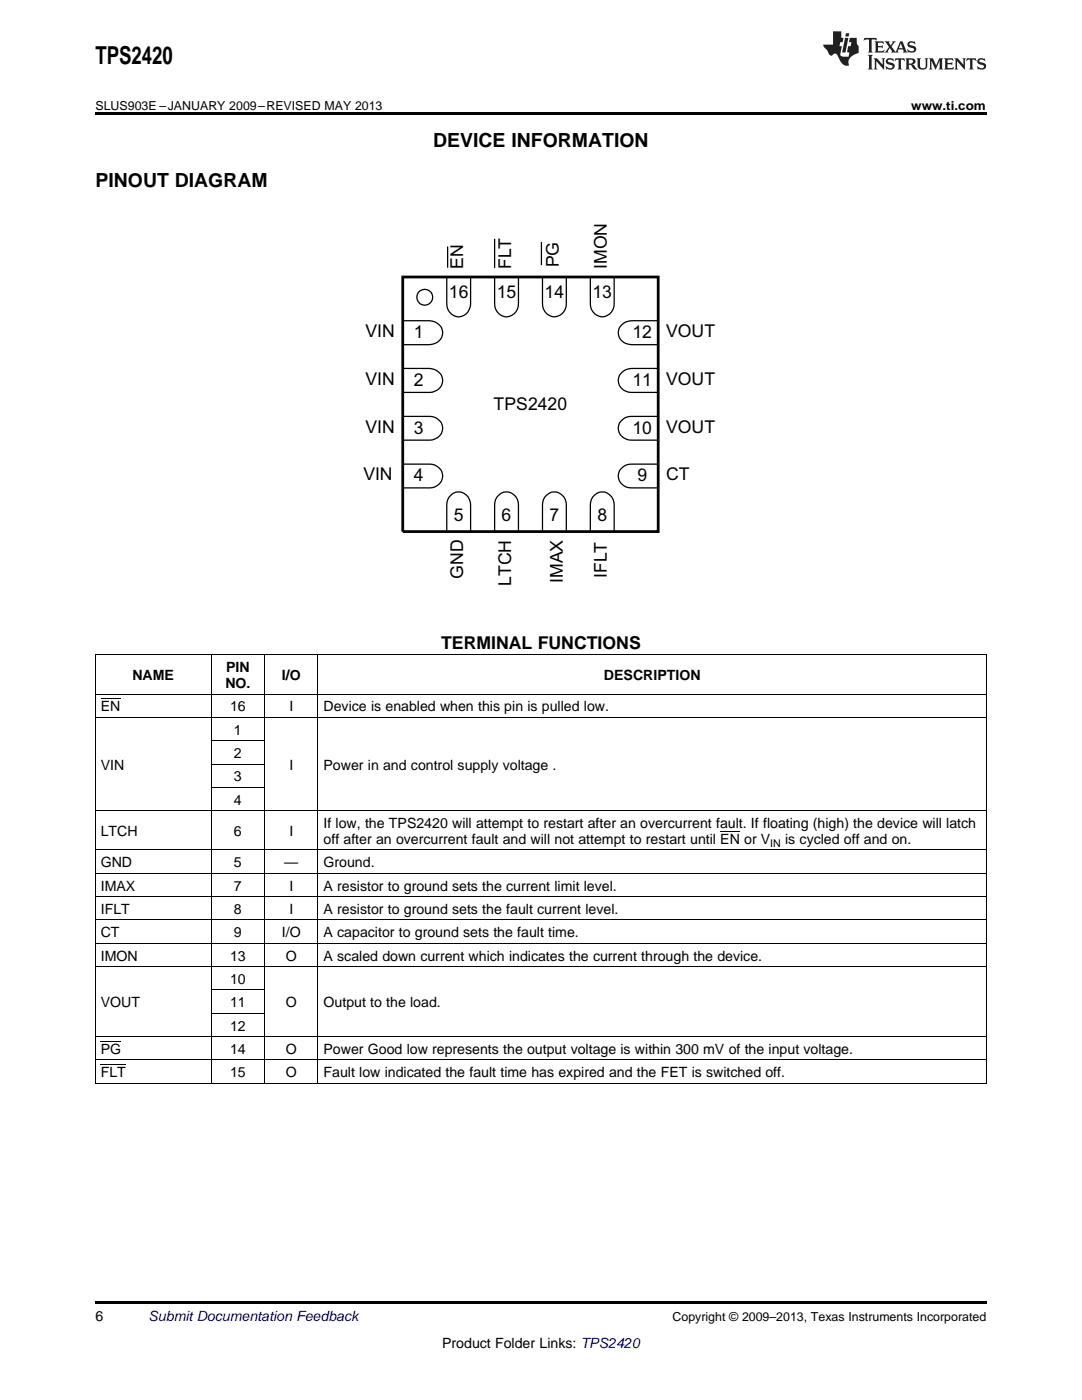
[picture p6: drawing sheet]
<svg xmlns="http://www.w3.org/2000/svg" width="216mm" height="279mm" viewBox="0 0 216 279" stroke-linecap="round" stroke-linejoin="round" font-family="sans-serif">
<defs><g id="words">
<text font-size="4.9" x="19" y="12.8">TPS2420</text>
<g font-size="3.9">
<text x="86.4" y="29.3">DEVICE INFORMATION</text>
<text x="19" y="37.4">PINOUT DIAGRAM</text>
</g>
<g font-size="3.5" fill="#010202">
<text x="92.4" y="53.7" transform="rotate(-90 92.4 53.7)">EN</text>
<text x="102" y="53.7" transform="rotate(-90 102 53.7)">FLT</text>
<text x="111.5" y="53.4" transform="rotate(-90 111.5 53.4)">PG</text>
<text x="121.1" y="53.7" transform="rotate(-90 121.1 53.7)">IMON</text>
<text x="89.6" y="59.5">16</text>
<text x="99.1" y="59.5">15</text>
<text x="108.7" y="59.5">14</text>
<text x="118.2" y="59.5">13</text>
<text x="72.9" y="67.3">VIN</text>
<text x="82.6" y="67.5">1</text>
<text x="126.2" y="67.5">12</text>
<text x="132.9" y="67.2">VOUT</text>
<text x="72.9" y="76.8">VIN</text>
<text x="82.6" y="77">2</text>
<text x="126.2" y="77">11</text>
<text x="132.9" y="76.9">VOUT</text>
<text x="98.5" y="81.7">TPS2420</text>
<text x="72.9" y="86.4">VIN</text>
<text x="82.6" y="86.5">3</text>
<text x="126.2" y="86.5">10</text>
<text x="132.9" y="86.4">VOUT</text>
<text x="72.5" y="95.9">VIN</text>
<text x="132.9" y="95.9">CT</text>
<text x="82.6" y="96.1">4</text>
<text x="127.2" y="96.1">9</text>
<text x="90.5" y="104">5</text>
<text x="100.1" y="104">6</text>
<text x="109.6" y="104">7</text>
<text x="119.2" y="104">8</text>
<text x="92.4" y="115.5" transform="rotate(-90 92.4 115.5)">GND</text>
<text x="102" y="116.9" transform="rotate(-90 102 116.9)">LTCH</text>
<text x="112.3" y="116.3" transform="rotate(-90 112.3 116.3)">IMAX</text>
<text x="121.1" y="115.4" transform="rotate(-90 121.1 115.4)">IFLT</text>
</g>
<text font-size="3.5" x="88" y="129.5">TERMINAL FUNCTIONS</text>
<g font-size="2.8">
<text x="26.4" y="135.7">NAME</text>
<text x="45" y="137.3">NO.</text>
<text x="45.1" y="134.1">PIN</text>
<text x="56.2" y="135.7">I/O</text>
<text x="120.5" y="135.7">DESCRIPTION</text>
<text x="20.1" y="142">EN</text>
<text x="45.9" y="142">16</text>
<text x="57.7" y="142">I</text>
<text x="64.6" y="142">Device is enabled when this pin is pulled low.</text>
<text x="46.7" y="146.6">1</text>
<text x="20.1" y="153.6">VIN</text>
<text x="46.7" y="151.3">2</text>
<text x="46.7" y="155.9">3</text>
<text x="57.7" y="153.6">I</text>
<text x="64.6" y="153.6">Power in and control supply voltage .</text>
<text x="46.7" y="160.6">4</text>
<text x="20.1" y="166.8">LTCH</text>
<text x="46.7" y="166.8">6</text>
<text x="57.7" y="166.8">I</text>
<text x="64.6" y="165.2">If low, the TPS2420 will attempt to restart after an overcurrent fault. If floating (high) the device will latch</text>
<text x="20.1" y="173.1">GND</text>
<text x="46.7" y="173.1">5</text>
<text x="56.7" y="173.1">—</text>
<text x="64.6" y="168.4">off after an overcurrent fault and will not attempt to restart until EN or V</text>
<text x="64.6" y="173.1">Ground.</text>
<text x="156.7" y="168.4">is cycled off and on.</text>
<text x="20.1" y="177.7">IMAX</text>
<text x="46.7" y="177.7">7</text>
<text x="57.7" y="177.7">I</text>
<text x="64.6" y="177.7">A resistor to ground sets the current limit level.</text>
<text x="20.1" y="182.4">IFLT</text>
<text x="46.7" y="182.4">8</text>
<text x="57.7" y="182.4">I</text>
<text x="64.6" y="182.4">A resistor to ground sets the fault current level.</text>
<text x="20.1" y="187">CT</text>
<text x="20.1" y="191.7">IMON</text>
<text x="45.9" y="191.7">13</text>
<text x="46.7" y="187">9</text>
<text x="56.2" y="187">I/O</text>
<text x="57" y="191.7">O</text>
<text x="64.6" y="187">A capacitor to ground sets the fault time.</text>
<text x="64.6" y="191.7">A scaled down current which indicates the current through the device.</text>
<text x="45.9" y="196.4">10</text>
<text x="20.1" y="201">VOUT</text>
<text x="45.9" y="201">11</text>
<text x="57" y="201">O</text>
<text x="64.6" y="201">Output to the load.</text>
<text x="45.9" y="205.7">12</text>
<text x="20.1" y="210.3">PG</text>
<text x="20.1" y="215">FLT</text>
<text x="45.9" y="210.3">14</text>
<text x="45.9" y="215">15</text>
<text x="57" y="210.3">O</text>
<text x="57" y="215">O</text>
<text x="64.6" y="210.3">Power Good low represents the output voltage is within 300 mV of the input voltage.</text>
<text x="64.6" y="215">Fault low indicated the fault time has expired and the FET is switched off.</text>
<text x="19" y="263.6">6</text>
<text x="88.2" y="269">Product Folder Links: TPS2420</text>
</g>
<text font-size="2.8" fill="#0000c8" x="29.6" y="263.6">Submit Documentation Feedback</text>
<g font-size="2.5">
<text x="19" y="21.9">SLUS903E –JANUARY 2009–REVISED MAY 2013</text>
<text x="181.8" y="21.9">www.ti.com</text>
<text x="134.2" y="263.6">Copyright © 2009–2013, Texas Instruments Incorporated</text>
</g>
<text font-size="2.1" x="153.7" y="169">IN</text>
</g></defs>
<path d="M19 22.5h177.8v.5h-177.8zM19 259.7h177.8v.5h-177.8z" fill="#000"/>
<g fill="none" stroke="#000" stroke-width=".2">
<path d="M19 138.5h177.8M19 130.7h177.8M19.1 130.7v85.6M42.1 130.7v85.6M52.8 130.7v85.6M63.4 130.7v85.6M196.8 130.7v85.6M19 143.2h177.8M42.2 157.1h10.6M42.2 152.5h10.6M42.2 147.8h10.6M19 178.9h177.8"/>
<path d="M19 174.3h177.8M19 169.6h177.8M19 161.8h177.8M19 192.9h177.8M19 188.3h177.8M19 183.6h177.8M42.2 197.6h10.6M19 216.2h177.8M19 211.5h177.8M19 206.9h177.8M42.2 202.2h10.6"/>
</g>
<path d="M80.4 55.3h50.9v50.8h-50.9z" fill="none" stroke="#010202" stroke-width=".55"/>
<g fill="none" stroke="#010202" stroke-width=".25">
<path d="M89.1 55.3v5.3a2.39 2.39 0 0 0 2.4 2.6 2.39 2.39 0 0 0 2.4-2.6v-5.3M89.3 49.2v4.2M98.7 55.3v5.3a2.39 2.39 0 0 0 2.4 2.6 2.39 2.39 0 0 0 2.4-2.6v-5.3M98.7 47.7v5.8M108 48.3v4.6M108.2 55.3v5.3a2.39 2.39 0 0 0 2.4 2.6 2.39 2.39 0 0 0 2.4-2.6v-5.3M117.8 55.3v5.3a2.39 2.39 0 0 0 2.4 2.6 2.39 2.39 0 0 0 2.4-2.6v-5.3M80.4 73.5h5.3a2.39 2.39 0 0 1 2.6 2.1 2.39 2.39 0 0 1-2 2.7h-5.9M80.4 64h5.3a2.37 2.37 0 0 1 2.6 2.1 2.37 2.37 0 0 1-2 2.6l-5.9 .1M131.3 64h-5.3a2.37 2.37 0 0 0-2.6 2.1 2.37 2.37 0 0 0 2 2.6l5.9 .1M131.3 73.5h-5.3a2.39 2.39 0 0 0-2.6 2.1 2.39 2.39 0 0 0 2 2.7h5.9M80.4 92.6h5.3a2.39 2.39 0 0 1 2.6 2.4 2.39 2.39 0 0 1-2.6 2.4h-5.3"/>
<path d="M80.4 83.1h5.3a2.37 2.37 0 0 1 2.6 2.1 2.37 2.37 0 0 1-2 2.6h-5.9M131.3 83.1h-5.3a2.39 2.39 0 0 0-2.6 2.4 2.39 2.39 0 0 0 2.6 2.3h5.3M131.3 92.6h-5.3a2.39 2.39 0 0 0-2.6 2.4 2.39 2.39 0 0 0 2.6 2.4h5.3M89.1 106.1v-5.3a2.39 2.39 0 0 1 2.4-2.6 2.39 2.39 0 0 1 2.4 2.6v5.3M98.7 106.1v-5.3a2.39 2.39 0 0 1 2.4-2.6 2.39 2.39 0 0 1 2.4 2.6v5.3M108.2 106.1v-5.3a2.39 2.39 0 0 1 2.4-2.6 2.39 2.39 0 0 1 2.4 2.6v5.3M117.8 106.1v-5.3a2.39 2.39 0 0 1 2.4-2.6 2.39 2.39 0 0 1 2.4 2.6v5.3"/>
<circle cx="84.8" cy="59.3" r="1.59"/>
</g>
<g fill="#231f20">
<path d="M172.5 7.6l-.1 .5 .4-.2h.6v.1v2.1l-.2 .4h.9l-.2-.4v-2.1l.1-.1h.5l.5 .2-.2-.5zM174.5 8.3l.2 .3v1.5l-.2 .4h1.8l.2-.6a1.04 1.04 0 0 1-1.3 .2v-.7h.6l.3 .2v-.6l-.3 .2h-.6v-.6l.8-.1 .4 .3-.2-.5zM176.5 8.3l.9 1.1-.9 1.1h.8l-.2-.2 .4-.7 .5 .7-.2 .2h1.5l-.2-.2 .2-.4h.9l.1 .4-.2 .2h1l-.3-.3-.7-1.9h-.5l-.9 2-.8-1 .9-1h-.8l.1 .3-.4 .5-.3-.6 .1-.2zM179.7 8.6l.4 1h-.7zM181.3 8.4a.63 .63 0 0 0-.2 .7 .63 .63 0 0 0 .6 .4l.6 .2 .1 .2a.75 .75 0 0 1-.7 .4 .75 .75 0 0 1-.6-.5l.1 .7 .1-.1a1.11 1.11 0 0 0 1.5-.6 1.13 1.13 0 0 0-1.2-.8l-.1-.4a1.04 1.04 0 0 1 1.2 .2l-.2-.5-.2 .1-.4-.2zM173.2 10.9l.2 .4v2.2l-.2 .4h1l-.3-.4v-2.2l.3-.4zM174.3 11.6l.3 .4v1.5l-.3 .4h.8l-.2-.4v-1.3l1.5 1.7v-1.9l.2-.4h-.7l.2 .4v.9l-1.1-1.3zM177 11.8a.62 .62 0 0 0-.2 .7 .62 .62 0 0 0 .6 .4l.6 .1 .1 .3a.76 .76 0 0 1-.7 .3 .76 .76 0 0 1-.7-.4l.2 .7 .1-.1a1.11 1.11 0 0 0 1.5-.6 1.13 1.13 0 0 0-1.2-.8l-.1-.4a1.04 1.04 0 0 1 1.2 .2l-.2-.6-.2 .1-.5-.1zM178.7 11.6l-.2 .6a.61 .61 0 0 1 .8-.3v1.6l-.2 .4h.9l-.2-.4v-1.6a.63 .63 0 0 1 .7 .3l-.1-.6zM180.6 11.6l.3 .4v1.5l-.3 .4h1l-.2-.2-.1-.8 .6 .2a.76 .76 0 0 0 1.2 .7l-1-1a.58 .58 0 0 0 .6-.5 .58 .58 0 0 0-.5-.6zM181.4 11.9h.1a.45 .45 0 0 1 .5 .1 .45 .45 0 0 1 .1 .5l-.8 .2zM182.9 11.6l.2 .2a2.17 2.17 0 0 0 .3 1.9 .99 .99 0 0 0 1.6-.6v-1.1l.2-.4h-.7l.2 .2a1.92 1.92 0 0 1-.2 1.8 .6 .6 0 0 1-.9-.5v-1.1l.2-.4zM185.4 11.6l.2 .4v1.5l-.2 .4h.7l-.2-.4v-1.4l.8 1.8 .8-1.8v1.4l-.2 .4h.9l-.2-.4v-1.5l.2-.4h-.8l-.6 1.5-.6-1.5zM188.4 11.6l.2 .4v1.5l-.2 .4h1.8l.1-.6a1.04 1.04 0 0 1-1.2 .1v-.6h.5l.4 .2v-.6l-.4 .2h-.5v-.7h.8l.3 .3-.1-.6zM190.5 11.6l.2 .4v1.5l-.2 .4h.7l-.2-.4v-1.3l1.5 1.7v-1.9l.2-.4h-.7l.2 .4v.9l-1.1-1.3zM192.9 11.6l-.1 .6a.61 .61 0 0 1 .7-.3l.1 1.6-.3 .4h1l-.3-.4 .1-1.6a.63 .63 0 0 1 .7 .3l-.1-.6zM195.2 11.8a.62 .62 0 0 0-.2 .7 .62 .62 0 0 0 .6 .4l.6 .1 .1 .3a.76 .76 0 0 1-.7 .3 .76 .76 0 0 1-.6-.4l.1 .7 .1-.1a1.11 1.11 0 0 0 1.6-.6 1.13 1.13 0 0 0-1.3-.8l-.1-.4a1.04 1.04 0 0 1 1.2 .2l-.1-.6-.2 .1-.5-.1z"/>
<path d="M166.2 6.3v2.6h-1.9v.4l.8 .9a.91 .91 0 0 0 1 .8 .56 .56 0 0 1 .5-.3 .56 .56 0 0 1 .5 .3l.4 .8a1.53 1.53 0 0 0 1.9 1.2 1.54 1.54 0 0 1 1-2.1l.9-.3v-1.4a1.52 1.52 0 0 1-.4-1.6h-1.3l-.2 .8h.5l-.2 .8h-.5l-.1 1v.2l.4 .1-.2 .8a1.93 1.93 0 0 1-1.6-.3l.3-1.8h-.5l.2-.8h.4l.2-.8h-.4v-1.3zM168.6 7.6l-.6 2.9h.7l.6-2.9zM168.8 6.6l-.1 .7h.6l.2-.7z"/>
</g>
<path d="M20.1 139.5h3.9M143.7 165.9h3.9M20.1 212.5h5M20.1 207.8h4.1" fill="none" stroke="#000" stroke-width=".2"/>
<use href="#words"/>
</svg>
